###############################################################
#  Generated by:      Cadence Innovus 21.10-p004_1
#  OS:                Linux x86_64(Host ID caen-vnc-mi07.engin.umich.edu)
#  Generated on:      Sat Mar 19 03:07:54 2022
#  Design:            mult_chip
#  Command:           write_lef_abstract /afs/umich.edu/class/eecs627/w23/template_prj/mult_chip/apr/data/mult_chip.lef -specifyTopLayer 8 -stripePin -PGpinLayers 8
###############################################################

VERSION 5.8 ;

BUSBITCHARS "[]" ;
DIVIDERCHAR "/" ;

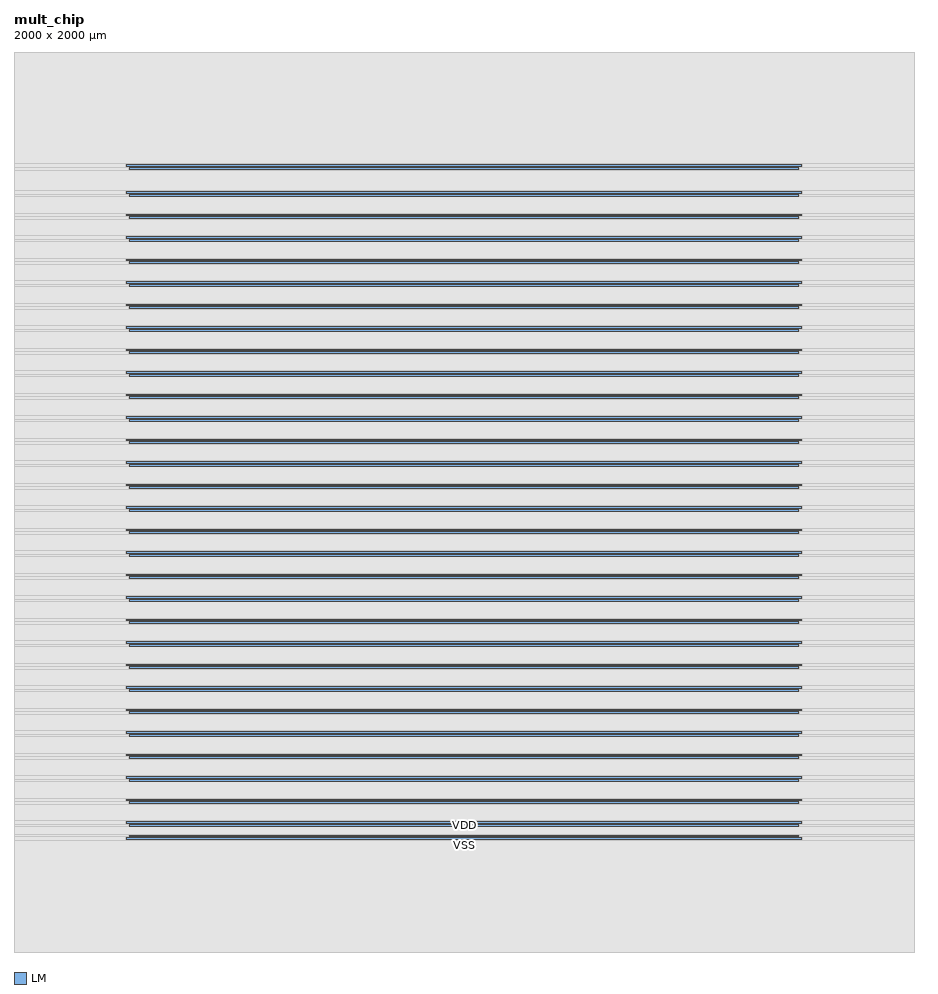
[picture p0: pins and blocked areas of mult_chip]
MACRO mult_chip
  CLASS BLOCK ;
  SIZE 2000.000000 BY 2000.000000 ;
  FOREIGN mult_chip 0.000000 0.000000 ;
  ORIGIN 0 0 ;
  SYMMETRY X Y R90 ;
  PIN i_clk
    DIRECTION INPUT ;
    USE SIGNAL ;
  END i_clk
  PIN i_reset
    DIRECTION INPUT ;
    USE SIGNAL ;
  END i_reset
  PIN i_smem_ext
    DIRECTION INPUT ;
    USE SIGNAL ;
  END i_smem_ext
  PIN i_smem_cen
    DIRECTION INPUT ;
    USE SIGNAL ;
  END i_smem_cen
  PIN i_smem_wen
    DIRECTION INPUT ;
    USE SIGNAL ;
  END i_smem_wen
  PIN i_smem_addr[11]
    DIRECTION INPUT ;
    USE SIGNAL ;
  END i_smem_addr[11]
  PIN i_smem_addr[10]
    DIRECTION INPUT ;
    USE SIGNAL ;
  END i_smem_addr[10]
  PIN i_smem_addr[9]
    DIRECTION INPUT ;
    USE SIGNAL ;
  END i_smem_addr[9]
  PIN i_smem_addr[8]
    DIRECTION INPUT ;
    USE SIGNAL ;
  END i_smem_addr[8]
  PIN i_smem_addr[7]
    DIRECTION INPUT ;
    USE SIGNAL ;
  END i_smem_addr[7]
  PIN i_smem_addr[6]
    DIRECTION INPUT ;
    USE SIGNAL ;
  END i_smem_addr[6]
  PIN i_smem_addr[5]
    DIRECTION INPUT ;
    USE SIGNAL ;
  END i_smem_addr[5]
  PIN i_smem_addr[4]
    DIRECTION INPUT ;
    USE SIGNAL ;
  END i_smem_addr[4]
  PIN i_smem_addr[3]
    DIRECTION INPUT ;
    USE SIGNAL ;
  END i_smem_addr[3]
  PIN i_smem_addr[2]
    DIRECTION INPUT ;
    USE SIGNAL ;
  END i_smem_addr[2]
  PIN i_smem_addr[1]
    DIRECTION INPUT ;
    USE SIGNAL ;
  END i_smem_addr[1]
  PIN i_smem_addr[0]
    DIRECTION INPUT ;
    USE SIGNAL ;
  END i_smem_addr[0]
  PIN i_smem_wdata[15]
    DIRECTION INPUT ;
    USE SIGNAL ;
  END i_smem_wdata[15]
  PIN i_smem_wdata[14]
    DIRECTION INPUT ;
    USE SIGNAL ;
  END i_smem_wdata[14]
  PIN i_smem_wdata[13]
    DIRECTION INPUT ;
    USE SIGNAL ;
  END i_smem_wdata[13]
  PIN i_smem_wdata[12]
    DIRECTION INPUT ;
    USE SIGNAL ;
  END i_smem_wdata[12]
  PIN i_smem_wdata[11]
    DIRECTION INPUT ;
    USE SIGNAL ;
  END i_smem_wdata[11]
  PIN i_smem_wdata[10]
    DIRECTION INPUT ;
    USE SIGNAL ;
  END i_smem_wdata[10]
  PIN i_smem_wdata[9]
    DIRECTION INPUT ;
    USE SIGNAL ;
  END i_smem_wdata[9]
  PIN i_smem_wdata[8]
    DIRECTION INPUT ;
    USE SIGNAL ;
  END i_smem_wdata[8]
  PIN i_smem_wdata[7]
    DIRECTION INPUT ;
    USE SIGNAL ;
  END i_smem_wdata[7]
  PIN i_smem_wdata[6]
    DIRECTION INPUT ;
    USE SIGNAL ;
  END i_smem_wdata[6]
  PIN i_smem_wdata[5]
    DIRECTION INPUT ;
    USE SIGNAL ;
  END i_smem_wdata[5]
  PIN i_smem_wdata[4]
    DIRECTION INPUT ;
    USE SIGNAL ;
  END i_smem_wdata[4]
  PIN i_smem_wdata[3]
    DIRECTION INPUT ;
    USE SIGNAL ;
  END i_smem_wdata[3]
  PIN i_smem_wdata[2]
    DIRECTION INPUT ;
    USE SIGNAL ;
  END i_smem_wdata[2]
  PIN i_smem_wdata[1]
    DIRECTION INPUT ;
    USE SIGNAL ;
  END i_smem_wdata[1]
  PIN i_smem_wdata[0]
    DIRECTION INPUT ;
    USE SIGNAL ;
  END i_smem_wdata[0]
  PIN o_smem_rdata[15]
    DIRECTION OUTPUT ;
    USE SIGNAL ;
  END o_smem_rdata[15]
  PIN o_smem_rdata[14]
    DIRECTION OUTPUT ;
    USE SIGNAL ;
  END o_smem_rdata[14]
  PIN o_smem_rdata[13]
    DIRECTION OUTPUT ;
    USE SIGNAL ;
  END o_smem_rdata[13]
  PIN o_smem_rdata[12]
    DIRECTION OUTPUT ;
    USE SIGNAL ;
  END o_smem_rdata[12]
  PIN o_smem_rdata[11]
    DIRECTION OUTPUT ;
    USE SIGNAL ;
  END o_smem_rdata[11]
  PIN o_smem_rdata[10]
    DIRECTION OUTPUT ;
    USE SIGNAL ;
  END o_smem_rdata[10]
  PIN o_smem_rdata[9]
    DIRECTION OUTPUT ;
    USE SIGNAL ;
  END o_smem_rdata[9]
  PIN o_smem_rdata[8]
    DIRECTION OUTPUT ;
    USE SIGNAL ;
  END o_smem_rdata[8]
  PIN o_smem_rdata[7]
    DIRECTION OUTPUT ;
    USE SIGNAL ;
  END o_smem_rdata[7]
  PIN o_smem_rdata[6]
    DIRECTION OUTPUT ;
    USE SIGNAL ;
  END o_smem_rdata[6]
  PIN o_smem_rdata[5]
    DIRECTION OUTPUT ;
    USE SIGNAL ;
  END o_smem_rdata[5]
  PIN o_smem_rdata[4]
    DIRECTION OUTPUT ;
    USE SIGNAL ;
  END o_smem_rdata[4]
  PIN o_smem_rdata[3]
    DIRECTION OUTPUT ;
    USE SIGNAL ;
  END o_smem_rdata[3]
  PIN o_smem_rdata[2]
    DIRECTION OUTPUT ;
    USE SIGNAL ;
  END o_smem_rdata[2]
  PIN o_smem_rdata[1]
    DIRECTION OUTPUT ;
    USE SIGNAL ;
  END o_smem_rdata[1]
  PIN o_smem_rdata[0]
    DIRECTION OUTPUT ;
    USE SIGNAL ;
  END o_smem_rdata[0]
  PIN VSS
    DIRECTION INOUT ;
    USE GROUND ;

# P/G power stripe data as pin
    PORT
      LAYER LM ;
        RECT 250.000000 250.000000 1750.000000 254.000000 ;
        RECT 250.000000 286.000000 1750.000000 290.000000 ;
        RECT 250.000000 336.000000 1750.000000 340.000000 ;
        RECT 250.000000 436.000000 1750.000000 440.000000 ;
        RECT 250.000000 386.000000 1750.000000 390.000000 ;
        RECT 250.000000 486.000000 1750.000000 490.000000 ;
        RECT 250.000000 536.000000 1750.000000 540.000000 ;
        RECT 250.000000 586.000000 1750.000000 590.000000 ;
        RECT 250.000000 686.000000 1750.000000 690.000000 ;
        RECT 250.000000 636.000000 1750.000000 640.000000 ;
        RECT 250.000000 736.000000 1750.000000 740.000000 ;
        RECT 250.000000 786.000000 1750.000000 790.000000 ;
        RECT 250.000000 836.000000 1750.000000 840.000000 ;
        RECT 250.000000 936.000000 1750.000000 940.000000 ;
        RECT 250.000000 886.000000 1750.000000 890.000000 ;
        RECT 250.000000 986.000000 1750.000000 990.000000 ;
        RECT 250.000000 1036.000000 1750.000000 1040.000000 ;
        RECT 250.000000 1086.000000 1750.000000 1090.000000 ;
        RECT 250.000000 1186.000000 1750.000000 1190.000000 ;
        RECT 250.000000 1136.000000 1750.000000 1140.000000 ;
        RECT 250.000000 1236.000000 1750.000000 1240.000000 ;
        RECT 250.000000 1286.000000 1750.000000 1290.000000 ;
        RECT 250.000000 1336.000000 1750.000000 1340.000000 ;
        RECT 250.000000 1436.000000 1750.000000 1440.000000 ;
        RECT 250.000000 1386.000000 1750.000000 1390.000000 ;
        RECT 250.000000 1486.000000 1750.000000 1490.000000 ;
        RECT 250.000000 1536.000000 1750.000000 1540.000000 ;
        RECT 250.000000 1586.000000 1750.000000 1590.000000 ;
        RECT 250.000000 1686.000000 1750.000000 1690.000000 ;
        RECT 250.000000 1636.000000 1750.000000 1640.000000 ;
        RECT 250.000000 1745.200000 1750.000000 1749.200000 ;
    END
# end of P/G power stripe data as pin

  END VSS
  PIN VDD
    DIRECTION INOUT ;
    USE POWER ;

# P/G power stripe data as pin
    PORT
      LAYER LM ;
        RECT 256.000000 280.000000 1744.000000 284.000000 ;
        RECT 256.000000 256.000000 1744.000000 260.000000 ;
        RECT 256.000000 330.000000 1744.000000 334.000000 ;
        RECT 256.000000 380.000000 1744.000000 384.000000 ;
        RECT 256.000000 430.000000 1744.000000 434.000000 ;
        RECT 256.000000 480.000000 1744.000000 484.000000 ;
        RECT 256.000000 530.000000 1744.000000 534.000000 ;
        RECT 256.000000 580.000000 1744.000000 584.000000 ;
        RECT 256.000000 630.000000 1744.000000 634.000000 ;
        RECT 256.000000 680.000000 1744.000000 684.000000 ;
        RECT 256.000000 730.000000 1744.000000 734.000000 ;
        RECT 256.000000 780.000000 1744.000000 784.000000 ;
        RECT 256.000000 830.000000 1744.000000 834.000000 ;
        RECT 256.000000 880.000000 1744.000000 884.000000 ;
        RECT 256.000000 930.000000 1744.000000 934.000000 ;
        RECT 256.000000 980.000000 1744.000000 984.000000 ;
        RECT 256.000000 1030.000000 1744.000000 1034.000000 ;
        RECT 256.000000 1080.000000 1744.000000 1084.000000 ;
        RECT 256.000000 1130.000000 1744.000000 1134.000000 ;
        RECT 256.000000 1180.000000 1744.000000 1184.000000 ;
        RECT 256.000000 1230.000000 1744.000000 1234.000000 ;
        RECT 256.000000 1280.000000 1744.000000 1284.000000 ;
        RECT 256.000000 1330.000000 1744.000000 1334.000000 ;
        RECT 256.000000 1380.000000 1744.000000 1384.000000 ;
        RECT 256.000000 1430.000000 1744.000000 1434.000000 ;
        RECT 256.000000 1480.000000 1744.000000 1484.000000 ;
        RECT 256.000000 1530.000000 1744.000000 1534.000000 ;
        RECT 256.000000 1580.000000 1744.000000 1584.000000 ;
        RECT 256.000000 1630.000000 1744.000000 1634.000000 ;
        RECT 256.000000 1680.000000 1744.000000 1684.000000 ;
        RECT 256.000000 1739.200000 1744.000000 1743.200000 ;
    END
# end of P/G power stripe data as pin

  END VDD
  OBS
    LAYER M1 ;
      RECT 0.000000 0.000000 2000.000000 2000.000000 ;
    LAYER M2 ;
      RECT 0.000000 0.000000 2000.000000 2000.000000 ;
    LAYER M3 ;
      RECT 0.000000 0.000000 2000.000000 2000.000000 ;
    LAYER M4 ;
      RECT 0.000000 0.000000 2000.000000 2000.000000 ;
    LAYER M5 ;
      RECT 0.000000 0.000000 2000.000000 2000.000000 ;
    LAYER M6 ;
      RECT 0.000000 0.000000 2000.000000 2000.000000 ;
    LAYER MQ ;
      RECT 0.000000 0.000000 2000.000000 2000.000000 ;
    LAYER LM ;
      RECT 0.000000 1751.120000 2000.000000 2000.000000 ;
      RECT 1751.920000 1743.280000 2000.000000 1751.120000 ;
      RECT 0.000000 1743.280000 248.080000 1751.120000 ;
      RECT 1745.920000 1737.280000 2000.000000 1743.280000 ;
      RECT 0.000000 1737.280000 254.080000 1743.280000 ;
      RECT 0.000000 1691.920000 2000.000000 1737.280000 ;
      RECT 1751.920000 1684.080000 2000.000000 1691.920000 ;
      RECT 0.000000 1684.080000 248.080000 1691.920000 ;
      RECT 1745.920000 1678.080000 2000.000000 1684.080000 ;
      RECT 0.000000 1678.080000 254.080000 1684.080000 ;
      RECT 0.000000 1641.920000 2000.000000 1678.080000 ;
      RECT 1751.920000 1634.080000 2000.000000 1641.920000 ;
      RECT 0.000000 1634.080000 248.080000 1641.920000 ;
      RECT 1745.920000 1628.080000 2000.000000 1634.080000 ;
      RECT 0.000000 1628.080000 254.080000 1634.080000 ;
      RECT 0.000000 1591.920000 2000.000000 1628.080000 ;
      RECT 1751.920000 1584.080000 2000.000000 1591.920000 ;
      RECT 0.000000 1584.080000 248.080000 1591.920000 ;
      RECT 1745.920000 1578.080000 2000.000000 1584.080000 ;
      RECT 0.000000 1578.080000 254.080000 1584.080000 ;
      RECT 0.000000 1541.920000 2000.000000 1578.080000 ;
      RECT 1751.920000 1534.080000 2000.000000 1541.920000 ;
      RECT 0.000000 1534.080000 248.080000 1541.920000 ;
      RECT 1745.920000 1528.080000 2000.000000 1534.080000 ;
      RECT 0.000000 1528.080000 254.080000 1534.080000 ;
      RECT 0.000000 1491.920000 2000.000000 1528.080000 ;
      RECT 1751.920000 1484.080000 2000.000000 1491.920000 ;
      RECT 0.000000 1484.080000 248.080000 1491.920000 ;
      RECT 1745.920000 1478.080000 2000.000000 1484.080000 ;
      RECT 0.000000 1478.080000 254.080000 1484.080000 ;
      RECT 0.000000 1441.920000 2000.000000 1478.080000 ;
      RECT 1751.920000 1434.080000 2000.000000 1441.920000 ;
      RECT 0.000000 1434.080000 248.080000 1441.920000 ;
      RECT 1745.920000 1428.080000 2000.000000 1434.080000 ;
      RECT 0.000000 1428.080000 254.080000 1434.080000 ;
      RECT 0.000000 1391.920000 2000.000000 1428.080000 ;
      RECT 1751.920000 1384.080000 2000.000000 1391.920000 ;
      RECT 0.000000 1384.080000 248.080000 1391.920000 ;
      RECT 1745.920000 1378.080000 2000.000000 1384.080000 ;
      RECT 0.000000 1378.080000 254.080000 1384.080000 ;
      RECT 0.000000 1341.920000 2000.000000 1378.080000 ;
      RECT 1751.920000 1334.080000 2000.000000 1341.920000 ;
      RECT 0.000000 1334.080000 248.080000 1341.920000 ;
      RECT 1745.920000 1328.080000 2000.000000 1334.080000 ;
      RECT 0.000000 1328.080000 254.080000 1334.080000 ;
      RECT 0.000000 1291.920000 2000.000000 1328.080000 ;
      RECT 1751.920000 1284.080000 2000.000000 1291.920000 ;
      RECT 0.000000 1284.080000 248.080000 1291.920000 ;
      RECT 1745.920000 1278.080000 2000.000000 1284.080000 ;
      RECT 0.000000 1278.080000 254.080000 1284.080000 ;
      RECT 0.000000 1241.920000 2000.000000 1278.080000 ;
      RECT 1751.920000 1234.080000 2000.000000 1241.920000 ;
      RECT 0.000000 1234.080000 248.080000 1241.920000 ;
      RECT 1745.920000 1228.080000 2000.000000 1234.080000 ;
      RECT 0.000000 1228.080000 254.080000 1234.080000 ;
      RECT 0.000000 1191.920000 2000.000000 1228.080000 ;
      RECT 1751.920000 1184.080000 2000.000000 1191.920000 ;
      RECT 0.000000 1184.080000 248.080000 1191.920000 ;
      RECT 1745.920000 1178.080000 2000.000000 1184.080000 ;
      RECT 0.000000 1178.080000 254.080000 1184.080000 ;
      RECT 0.000000 1141.920000 2000.000000 1178.080000 ;
      RECT 1751.920000 1134.080000 2000.000000 1141.920000 ;
      RECT 0.000000 1134.080000 248.080000 1141.920000 ;
      RECT 1745.920000 1128.080000 2000.000000 1134.080000 ;
      RECT 0.000000 1128.080000 254.080000 1134.080000 ;
      RECT 0.000000 1091.920000 2000.000000 1128.080000 ;
      RECT 1751.920000 1084.080000 2000.000000 1091.920000 ;
      RECT 0.000000 1084.080000 248.080000 1091.920000 ;
      RECT 1745.920000 1078.080000 2000.000000 1084.080000 ;
      RECT 0.000000 1078.080000 254.080000 1084.080000 ;
      RECT 0.000000 1041.920000 2000.000000 1078.080000 ;
      RECT 1751.920000 1034.080000 2000.000000 1041.920000 ;
      RECT 0.000000 1034.080000 248.080000 1041.920000 ;
      RECT 1745.920000 1028.080000 2000.000000 1034.080000 ;
      RECT 0.000000 1028.080000 254.080000 1034.080000 ;
      RECT 0.000000 991.920000 2000.000000 1028.080000 ;
      RECT 1751.920000 984.080000 2000.000000 991.920000 ;
      RECT 0.000000 984.080000 248.080000 991.920000 ;
      RECT 1745.920000 978.080000 2000.000000 984.080000 ;
      RECT 0.000000 978.080000 254.080000 984.080000 ;
      RECT 0.000000 941.920000 2000.000000 978.080000 ;
      RECT 1751.920000 934.080000 2000.000000 941.920000 ;
      RECT 0.000000 934.080000 248.080000 941.920000 ;
      RECT 1745.920000 928.080000 2000.000000 934.080000 ;
      RECT 0.000000 928.080000 254.080000 934.080000 ;
      RECT 0.000000 891.920000 2000.000000 928.080000 ;
      RECT 1751.920000 884.080000 2000.000000 891.920000 ;
      RECT 0.000000 884.080000 248.080000 891.920000 ;
      RECT 1745.920000 878.080000 2000.000000 884.080000 ;
      RECT 0.000000 878.080000 254.080000 884.080000 ;
      RECT 0.000000 841.920000 2000.000000 878.080000 ;
      RECT 1751.920000 834.080000 2000.000000 841.920000 ;
      RECT 0.000000 834.080000 248.080000 841.920000 ;
      RECT 1745.920000 828.080000 2000.000000 834.080000 ;
      RECT 0.000000 828.080000 254.080000 834.080000 ;
      RECT 0.000000 791.920000 2000.000000 828.080000 ;
      RECT 1751.920000 784.080000 2000.000000 791.920000 ;
      RECT 0.000000 784.080000 248.080000 791.920000 ;
      RECT 1745.920000 778.080000 2000.000000 784.080000 ;
      RECT 0.000000 778.080000 254.080000 784.080000 ;
      RECT 0.000000 741.920000 2000.000000 778.080000 ;
      RECT 1751.920000 734.080000 2000.000000 741.920000 ;
      RECT 0.000000 734.080000 248.080000 741.920000 ;
      RECT 1745.920000 728.080000 2000.000000 734.080000 ;
      RECT 0.000000 728.080000 254.080000 734.080000 ;
      RECT 0.000000 691.920000 2000.000000 728.080000 ;
      RECT 1751.920000 684.080000 2000.000000 691.920000 ;
      RECT 0.000000 684.080000 248.080000 691.920000 ;
      RECT 1745.920000 678.080000 2000.000000 684.080000 ;
      RECT 0.000000 678.080000 254.080000 684.080000 ;
      RECT 0.000000 641.920000 2000.000000 678.080000 ;
      RECT 1751.920000 634.080000 2000.000000 641.920000 ;
      RECT 0.000000 634.080000 248.080000 641.920000 ;
      RECT 1745.920000 628.080000 2000.000000 634.080000 ;
      RECT 0.000000 628.080000 254.080000 634.080000 ;
      RECT 0.000000 591.920000 2000.000000 628.080000 ;
      RECT 1751.920000 584.080000 2000.000000 591.920000 ;
      RECT 0.000000 584.080000 248.080000 591.920000 ;
      RECT 1745.920000 578.080000 2000.000000 584.080000 ;
      RECT 0.000000 578.080000 254.080000 584.080000 ;
      RECT 0.000000 541.920000 2000.000000 578.080000 ;
      RECT 1751.920000 534.080000 2000.000000 541.920000 ;
      RECT 0.000000 534.080000 248.080000 541.920000 ;
      RECT 1745.920000 528.080000 2000.000000 534.080000 ;
      RECT 0.000000 528.080000 254.080000 534.080000 ;
      RECT 0.000000 491.920000 2000.000000 528.080000 ;
      RECT 1751.920000 484.080000 2000.000000 491.920000 ;
      RECT 0.000000 484.080000 248.080000 491.920000 ;
      RECT 1745.920000 478.080000 2000.000000 484.080000 ;
      RECT 0.000000 478.080000 254.080000 484.080000 ;
      RECT 0.000000 441.920000 2000.000000 478.080000 ;
      RECT 1751.920000 434.080000 2000.000000 441.920000 ;
      RECT 0.000000 434.080000 248.080000 441.920000 ;
      RECT 1745.920000 428.080000 2000.000000 434.080000 ;
      RECT 0.000000 428.080000 254.080000 434.080000 ;
      RECT 0.000000 391.920000 2000.000000 428.080000 ;
      RECT 1751.920000 384.080000 2000.000000 391.920000 ;
      RECT 0.000000 384.080000 248.080000 391.920000 ;
      RECT 1745.920000 378.080000 2000.000000 384.080000 ;
      RECT 0.000000 378.080000 254.080000 384.080000 ;
      RECT 0.000000 341.920000 2000.000000 378.080000 ;
      RECT 1751.920000 334.080000 2000.000000 341.920000 ;
      RECT 0.000000 334.080000 248.080000 341.920000 ;
      RECT 1745.920000 328.080000 2000.000000 334.080000 ;
      RECT 0.000000 328.080000 254.080000 334.080000 ;
      RECT 0.000000 291.920000 2000.000000 328.080000 ;
      RECT 1751.920000 284.080000 2000.000000 291.920000 ;
      RECT 0.000000 284.080000 248.080000 291.920000 ;
      RECT 1745.920000 278.080000 2000.000000 284.080000 ;
      RECT 0.000000 278.080000 254.080000 284.080000 ;
      RECT 0.000000 261.920000 2000.000000 278.080000 ;
      RECT 1745.920000 255.920000 2000.000000 261.920000 ;
      RECT 0.000000 255.920000 254.080000 261.920000 ;
      RECT 1751.920000 248.080000 2000.000000 255.920000 ;
      RECT 0.000000 248.080000 248.080000 255.920000 ;
      RECT 0.000000 0.000000 2000.000000 248.080000 ;
  END
END mult_chip

END LIBRARY
